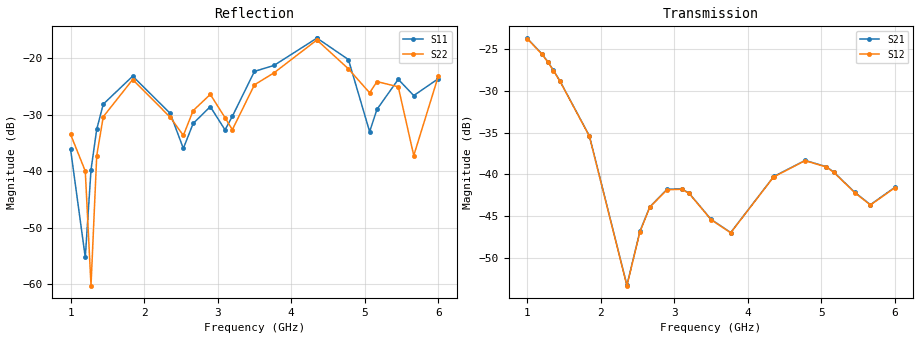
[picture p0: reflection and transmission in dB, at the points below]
!Agilent Technologies,E8364B,MY43040528,A.07.50.67
!Agilent E8364B: A.07.50.67
!Date: Sunday, March 01, 2026 16:31:09
!Correction: S11(Full 2 Port(1,2))
!S21(Full 2 Port(1,2))
!S12(Full 2 Port(1,2))
!S22(Full 2 Port(1,2))
!S2P File: Measurements: S11, S21, S12, S22:
# Hz S  dB  R 50
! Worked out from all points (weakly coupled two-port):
!   451 points, 1 GHz to 6 GHz, reference 50 ohm
!   highest |S21| = -23.74 dB at 1 GHz (marker M1); lowest = -53.2 dB at 2.356 GHz (marker M2)
!   lowest |S11| = -55.2 dB at 1.2 GHz (marker M3), VSWR 1.00, Z = 50.1 - j0.146 ohm
!   |S11| at or under -10 dB: start of sweep to end of sweep
!   |S22| runs from -60.2 to -16.8 dB; largest |S21 - S12| = 0.00028
!   S11 on the Smith chart (normalised r, x): 1 GHz: 1.03, +0.01; 4.356 GHz: 1.20, -0.26; 6 GHz: 0.97, -0.13
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1e9  -36.11 23.2  -23.74 153.1  -23.78 153.2  -33.48 -2.5
1.2e9  -55.23 -57.2  -25.60 38.8  -25.64 38.8  -39.98 -7.9
1.277778e9  -39.74 -145.1  -26.51 -5.4  -26.55 -5.3  -60.22 37.5
1.355556e9  -32.57 -164.9  -27.55 -49.0  -27.58 -48.9  -37.23 118.9
1.444444e9  -28.14 171.4  -28.83 -97.9  -28.86 -98.0  -30.36 96.7
1.844444e9  -23.19 87.3  -35.39 47.6  -35.42 47.7  -23.79 -4.9
2.355556e9  -29.78 25.5  -53.23 -149.2  -53.29 -149.2  -30.46 -83.9
2.533333e9  -35.97 50.4  -46.76 169.2  -46.82 169.3  -33.67 -61.3
2.666667e9  -31.55 76.5  -43.87 104.5  -43.91 104.6  -29.28 -58.1
2.9e9  -28.58 48.3  -41.78 -17.7  -41.83 -17.6  -26.41 -104.3
3.1e9  -32.68 55.1  -41.72 -124.0  -41.77 -124.0  -30.53 -135.0
3.2e9  -30.28 78.0  -42.23 -176.7  -42.26 -176.6  -32.65 -119.1
3.5e9  -22.35 50.7  -45.37 37.3  -45.41 37.4  -24.72 -127.9
3.766667e9  -21.29 25.8  -46.94 -65.9  -46.97 -65.8  -22.60 -155.7
4.344444e9  -16.51 -43.6  -40.33 22.4  -40.36 22.5  -16.84 111.4
4.355556e9  -16.51 -45.3  -40.23 16.5  -40.28 16.5  -16.87 109.2
4.777778e9  -20.25 -115.0  -38.32 140.0  -38.35 140.1  -21.89 35.1
5.066667e9  -33.00 -105.8  -39.07 -30.2  -39.11 -30.2  -26.13 45.1
5.166667e9  -29.05 -68.2  -39.70 -90.6  -39.74 -90.6  -24.15 38.8
5.455556e9  -23.75 -101.6  -42.15 85.9  -42.19 85.9  -25.07 -20.1
5.666667e9  -26.62 -111.5  -43.61 -63.0  -43.65 -63.1  -37.22 -7.2
6e9  -23.64 -100.5  -41.53 59.8  -41.58 59.8  -23.22 -0.7
